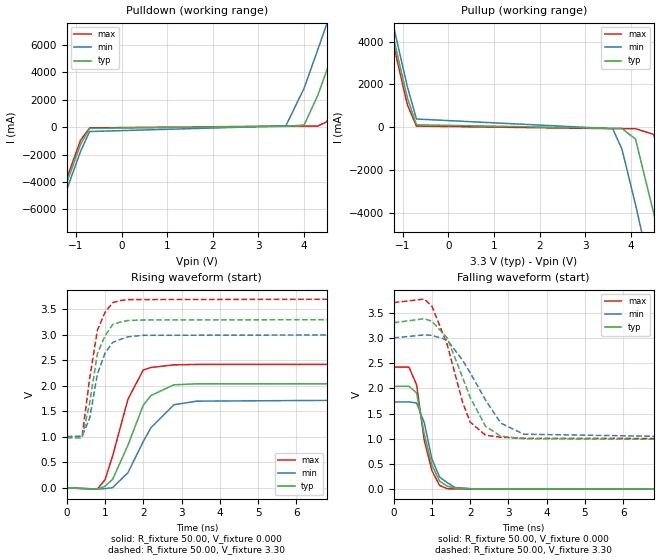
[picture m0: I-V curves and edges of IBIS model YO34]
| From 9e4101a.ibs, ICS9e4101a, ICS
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|   Model YO34
[Model]   YO34
Model_type   Output
Polarity   Non-Inverting
C_comp   5.50pF   5.00pF   6.00pF
[Temperature Range]   27.00   70.00   0.000
[Voltage Range]   3.30V   3.00V   3.70V
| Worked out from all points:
|   slope of the pulldown table from 0 to 0.495 V, typ, clamps not added: 18 ohm
|   slope of the pullup table from 0 to 0.495 V, typ, clamps not added: 25.6 ohm
|   rising waveform, R_fixture 50.00, V_fixture 0.000: 20-80 % time 643ps typ, 791ps min, 581ps max; typ from 0 V to 2.04 V
|   rising waveform, R_fixture 50.00, V_fixture 3.30: 20-80 % time 383ps typ, 373ps min, 347ps max; typ from 0.98 V to 3.3 V
|   falling waveform, R_fixture 50.00, V_fixture 0.000: 20-80 % time 377ps typ, 374ps min, 338ps max; typ from 2.04 V to 0 V
|   falling waveform, R_fixture 50.00, V_fixture 3.30: 20-80 % time 738ps typ, 947ps min, 636ps max; typ from 3.3 V to 0.98 V
[Pulldown]
| voltage   I(typ)   I(min)   I(max)
-3.3V     -24.5A     -25.12A    -24.2A
-1.7V     -8.77A     -9.29A     -8.45A
-1.5V     -6.83A     -7.35A     -6.51A
-900mV    -1.27A     -1.78A     -970mA
-700mV    -92.33mA   -320mA     -53mA
3.6V      62.06mA    88.77mA    76.48mA
4V        150mA      2.83A      76.72mA
4.3V      2.31A      5.64A      77.26mA
4.5V      4.16A      7.55A      400mA
4.9V      8A         11.44A     3.83A
5.3V      11.9A      15.36A     7.68A
6.6V      24.75A     28.22A     20.49A
[Pullup]
| voltage   I(typ)   I(min)   I(max)
-3.3V     24.61A     25.12A     24.3A
-1.7V     8.88A      9.42A      8.55A
-1.5V     6.94A      7.49A      6.61A
-900mV    1.37A      1.9A       1.05A
-700mV    110mA      380mA      48.51mA
3.6V      -57.33mA   -72.21mA   -72.12mA
3.8V      -57.8mA    -1.01A     -72.62mA
4.1V      -560mA     -3.62A     -73.3mA
4.5V      -4.04A     -7.42A     -340mA
4.9V      -7.88A     -11.31A    -3.72A
5.3V      -11.78A    -15.23A    -7.57A
6.6V      -24.64A    -28.1A     -20.38A
[Ramp]
| variable   typ   min   max
dV/dt_r   1.23/0.63n   1.04/0.78n   1.45/0.50n
dV/dt_f   1.39/0.73n   1.19/0.94n   1.62/0.58n
R_load = 50.00
[Rising Waveform]
R_fixture = 50.00
V_fixture = 0.000
V_fixture_min = 0.000
V_fixture_max = 0.000
| time   V(typ)   V(min)   V(max)
0s        0V         130uV      260uV
800ps     -21.29mV   -24.18mV   -20.91mV
1ns       32.3mV     -13.99mV   160mV
1.2ns     170mV      5.7mV      630mV
1.6ns     840mV      300mV      1.74V
2ns       1.62V      910mV      2.31V
2.2ns     1.81V      1.18V      2.36V
2.8ns     2.02V      1.63V      2.41V
3.4ns     2.04V      1.7V       2.42V
10ns      2.04V      1.73V      2.42V
[Rising Waveform]
R_fixture = 50.00
V_fixture = 3.30
V_fixture_min = 3.00
V_fixture_max = 3.70
| time   V(typ)   V(min)   V(max)
0s        980mV      1.01V      1V
400ps     980mV      1.01V      1.01V
600ps     1.67V      1.37V      2.15V
800ps     2.63V      2.23V      3.09V
1ns       2.98V      2.64V      3.44V
1.2ns     3.2V       2.85V      3.63V
1.4ns     3.25V      2.91V      3.67V
1.6ns     3.28V      2.96V      3.69V
2ns       3.29V      2.99V      3.69V
10ns      3.3V       3V         3.7V
[Falling Waveform]
R_fixture = 50.00
V_fixture = 0.000
V_fixture_min = 0.000
V_fixture_max = 0.000
| time   V(typ)   V(min)   V(max)
0s        2.04V      1.73V      2.42V
400ps     2.04V      1.73V      2.42V
600ps     1.91V      1.71V      2.07V
800ps     1.09V      1.32V      970mV
1ns       480mV      600mV      370mV
1.2ns     160mV      240mV      74.26mV
1.4ns     60.86mV    130mV      10.1mV
1.6ns     17.76mV    33.58mV    2.93mV
2.2ns     2.17mV     1.49mV     1.69mV
10ns      2.03uV     -5.17uV    -710nV
[Falling Waveform]
R_fixture = 50.00
V_fixture = 3.30
V_fixture_min = 3.00
V_fixture_max = 3.70
| time   V(typ)   V(min)   V(max)
0s        3.3V       3V         3.7V
800ps     3.38V      3.06V      3.77V
1ns       3.33V      3.05V      3.63V
1.4ns     3V         2.96V      2.87V
1.8ns     2.22V      2.56V      1.73V
2ns       1.82V      2.31V      1.33V
2.4ns     1.25V      1.77V      1.07V
2.8ns     1.05V      1.31V      1.03V
3.4ns     1V         1.09V      1.01V
10ns      980mV      1.01V      1V
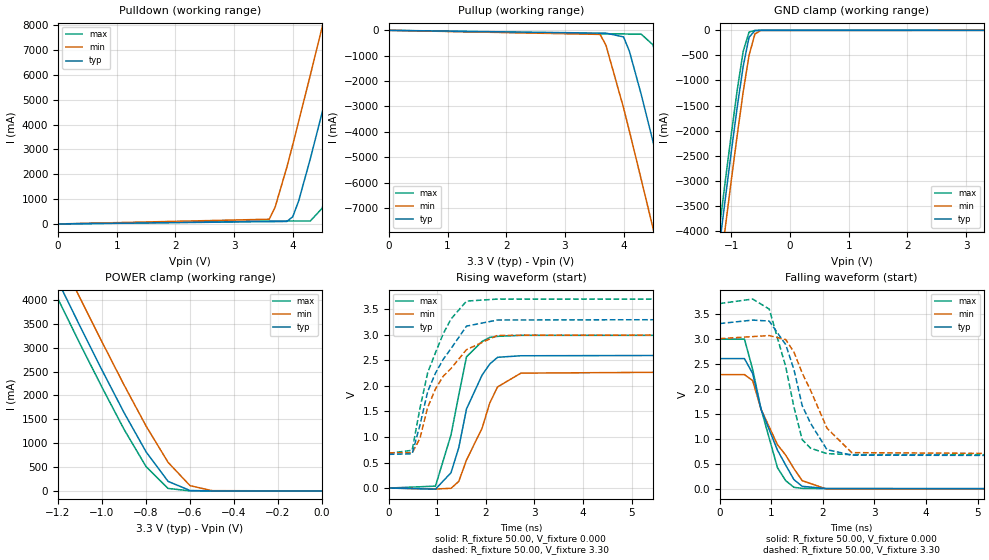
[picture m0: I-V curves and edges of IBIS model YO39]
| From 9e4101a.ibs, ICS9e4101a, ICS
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|   Model YO39
[Model]   YO39
Model_type   Output
Polarity   Non-Inverting
C_comp   5.50pF   5.00pF   6.00pF
[Temperature Range]   27.00   70.00   0.000
[Voltage Range]   3.30V   3.00V   3.70V
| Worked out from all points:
|   slope of the pulldown table from 0 to 0.495 V, typ, clamps not added: 11.9 ohm
|   slope of the pullup table from 0 to 0.495 V, typ, clamps not added: 12.9 ohm
|   GND clamp passes 1 mA (typ) near -0.51 V on its own axis
|   POWER clamp passes 1 mA (typ) near -0.51 V on its own axis
|   rising waveform, R_fixture 50.00, V_fixture 0.000: 20-80 % time 485ps typ, 595ps min, 418ps max; typ from 0 V to 2.6 V
|   rising waveform, R_fixture 50.00, V_fixture 3.30: 20-80 % time 678ps typ, 775ps min, 576ps max; typ from 0.66 V to 3.3 V
|   falling waveform, R_fixture 50.00, V_fixture 0.000: 20-80 % time 564ps typ, 672ps min, 437ps max; typ from 2.6 V to 0 V
|   falling waveform, R_fixture 50.00, V_fixture 3.30: 20-80 % time 508ps typ, 603ps min, 431ps max; typ from 3.3 V to 0.66 V
[Pulldown]
| voltage   I(typ)   I(min)   I(max)
|  -3.30   0.000A   0.000A   0.000A
|  -3.10   0.000A   0.000A   0.000A
|  -2.90   0.000A   0.000A   0.000A
|  -2.70   0.000A   0.000A   0.000A
|  -2.50   -10.00mA   0.000A   0.000A
|  -2.30   0.000A   0.000A   0.000A
|  -2.10   0.000A   0.000A   0.000A
|  -1.90   0.000A   0.000A   0.000A
|  -1.70   -1.00mA   -1.00mA   -1.00mA
|  -1.50   -2.00mA   -2.00mA   -2.00mA
|  -1.00   -6.00mA   -4.00mA   -7.00mA
|  -0.90   -9.00mA   -6.00mA   -12.00mA
|  -0.80   -16.50mA   -10.00mA   -25.10mA
|  -0.70   -38.70mA   -18.40mA   -57.51mA
|  -0.60   -52.20mA   -37.04mA   -57.37mA
|  -0.50   -45.23mA   -39.54mA   -48.83mA
|  -0.40   -36.72mA   -32.40mA   -39.66mA
|  -0.30   -27.90mA   -24.55mA   -30.18mA
|  -0.20   -18.84mA   -16.51mA   -20.42mA
|  -0.10   -9.54mA   -8.33mA   -10.36mA
0V        10.5pA     3pA        19.5pA
3.6V      94.37mA    190mA      120mA
3.7V      94.46mA    680mA      120mA
3.9V      100mA      2.29A      120mA
4V        290mA      3.19A      120mA
4.1V      920mA      4.12A      120mA
4.3V      2.63A      6A         120mA
4.5V      4.48A      7.92A      630mA
4.7V      6.39A      9.86A      2.28A
4.9V      8.32A      11.8A      4.14A
5.3V      12.22A     15.72A     7.99A
6.6V      25.08A     28.58A     20.8A
[Pullup]
| voltage   I(typ)   I(min)   I(max)
|  -3.30   0.000A   0.000A   0.000A
|  -3.10   0.000A   0.000A   0.000A
|  -2.90   0.000A   0.000A   0.000A
|  -2.70   0.000A   0.000A   0.000A
|  -2.50   0.000A   10.00mA   10.00mA
|  -2.30   0.000A   0.000A   0.000A
|  -2.10   0.000A   0.000A   0.000A
|  -1.90   10.00mA   0.000A   0.000A
|  -1.70   1.00mA   1.00mA   1.00mA
|  -1.50   2.00mA   1.00mA   2.00mA
|  -1.00   6.00mA   5.00mA   8.00mA
|  -0.90   8.00mA   6.00mA   11.00mA
|  -0.80   15.10mA   10.00mA   23.10mA
|  -0.70   33.90mA   16.30mA   55.01mA
|  -0.60   50.90mA   33.20mA   57.47mA
|  -0.50   43.82mA   38.39mA   48.08mA
|  -0.40   34.96mA   31.14mA   38.43mA
|  -0.30   26.11mA   23.19mA   28.78mA
|  -0.20   17.32mA   15.32mA   19.15mA
|  -0.10   8.60mA   7.58mA   9.54mA
0V        8.2pA      7.8pA      7pA
3.6V      -110mA     -160mA     -140mA
3.7V      -110mA     -590mA     -140mA
4V        -260mA     -3.06A     -140mA
4.1V      -830mA     -3.98A     -150mA
4.3V      -2.52A     -5.87A     -150mA
4.5V      -4.37A     -7.78A     -570mA
4.7V      -6.28A     -9.72A     -2.2A
4.9V      -8.21A     -11.66A    -4.05A
5.1V      -10.15A    -13.61A    -5.95A
5.3V      -12.1A     -15.57A    -7.89A
6.6V      -24.92A    -28.4A     -20.66A
[GND_clamp]
| voltage   I(typ)   I(min)   I(max)
-3.3V     -24.8A     -25.33A    -24.46A
-1.2V     -4.25A     -4.83A     -3.9A
-1.1V     -3.32A     -3.89A     -2.96A
-1V       -2.4A      -2.97A     -2.05A
-900mV    -1.52A     -2.08A     -1.18A
-800mV    -720mA     -1.23A     -420mA
-700mV    -140mA     -500mA     -34.66mA
-600mV    -5.87mA    -73.46mA   -1.13mA
-500mV    -230uA     -3.4mA     -71.58uA
3.3V      190pA      6.91uA     130pA
[POWER_clamp]
| voltage   I(typ)   I(min)   I(max)
-3.3V     24.94A     25.5A      24.6A
-1.3V     5.34A      5.93A      4.97A
-1.2V     4.39A      4.98A      4.02A
-1.1V     3.45A      4.04A      3.08A
-1V       2.53A      3.12A      2.17A
-900mV    1.64A      2.22A      1.29A
-800mV    820mA      1.36A      510mA
-700mV    200mA      600mA      51.99mA
-600mV    8.81mA     110mA      970uA
-500mV    200uA      5.57mA     14.89uA
0V        190pA      840pA      190pA
[Ramp]
| variable   typ   min   max
dV/dt_r   1.56/0.45n   1.37/0.54n   1.79/0.39n
dV/dt_f   1.58/0.48n   1.39/0.56n   1.81/0.38n
R_load = 50.00
[Rising Waveform]
R_fixture = 50.00
V_fixture = 0.000
V_fixture_min = 0.000
V_fixture_max = 0.000
| time   V(typ)   V(min)   V(max)
0s        0V         0V         0V
960ps     -21.72mV   -18.13mV   37.84mV
1.28ns    300mV      -5.22mV    1.04V
1.44ns    790mV      130mV      1.82V
1.6ns     1.55V      550mV      2.57V
1.92ns    2.21V      1.17V      2.87V
2.08ns    2.43V      1.67V      2.95V
2.24ns    2.56V      1.98V      2.97V
2.72ns    2.59V      2.25V      2.99V
8ns       2.6V       2.28V      2.99V
[Rising Waveform]
R_fixture = 50.00
V_fixture = 3.30
V_fixture_min = 3.00
V_fixture_max = 3.70
| time   V(typ)   V(min)   V(max)
0s        660mV      690mV      680mV
480ps     670mV      690mV      740mV
640ps     1.23V      970mV      1.56V
800ps     1.89V      1.58V      2.26V
960ps     2.25V      1.94V      2.65V
1.12ns    2.52V      2.19V      3.02V
1.28ns    2.73V      2.34V      3.31V
1.6ns     3.17V      2.71V      3.66V
2.24ns    3.29V      2.99V      3.7V
8ns       3.3V       3V         3.7V
[Falling Waveform]
R_fixture = 50.00
V_fixture = 0.000
V_fixture_min = 0.000
V_fixture_max = 0.000
| time   V(typ)   V(min)   V(max)
0s        2.6V       2.28V      2.99V
480ps     2.6V       2.28V      2.99V
640ps     2.3V       2.16V      2.38V
800ps     1.59V      1.59V      1.6V
1.12ns    770mV      880mV      420mV
1.28ns    470mV      670mV      160mV
1.44ns    180mV      400mV      26.48mV
1.6ns     46.55mV    160mV      6.41mV
2.08ns    1.75mV     -10.06mV   650uV
8ns       -2.5uV     2.79uV     -15.66uV
[Falling Waveform]
R_fixture = 50.00
V_fixture = 3.30
V_fixture_min = 3.00
V_fixture_max = 3.70
| time   V(typ)   V(min)   V(max)
0s        3.3V       3V         3.7V
640ps     3.37V      3.04V      3.79V
960ps     3.35V      3.06V      3.59V
1.28ns    2.88V      2.98V      2.44V
1.44ns    2.38V      2.73V      1.63V
1.6ns     1.66V      2.31V      980mV
1.76ns    1.31V      1.97V      810mV
2.08ns    780mV      1.21V      700mV
2.56ns    670mV      720mV      680mV
8ns       660mV      690mV      680mV
